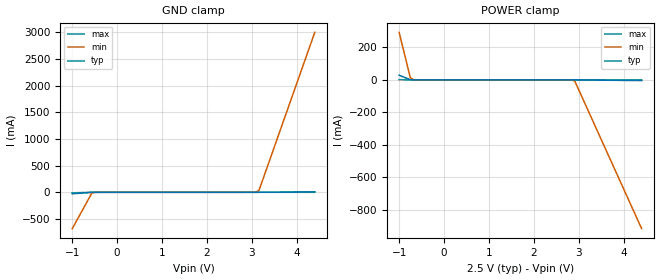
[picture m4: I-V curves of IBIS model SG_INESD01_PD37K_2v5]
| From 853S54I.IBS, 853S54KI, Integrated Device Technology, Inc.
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[Model] SG_INESD01_PD37K_2v5
Model_type   Input
Polarity   Non-Inverting
Vinl = 0.7V
Vinh = 1.7V
|   typ   min   max
C_comp   2pF   1.5pF   2.5pF
|   typ   min   max
[Voltage range]   2.5V   2.375V   2.625V
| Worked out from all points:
|   GND clamp passes 1 mA (typ) near -0.54 V on its own axis
|   POWER clamp passes 1 mA (typ) near -0.74 V on its own axis
[GND_clamp]
|Voltage   I (typ)   I (min)   I (max)
-999mV    -27.96mA   -681.8mA   -9.625mA
-564.6mV  -1.482mA   -16.24mA   -666.5uA
-502.5mV  -453.5uA   -2.74mA    -140.7uA
2.973V    79.17uA    336.2uA    73.41uA
3.097V    110.7uA    5.854mA    76.48uA
3.159V    212.3uA    36.85mA    78.12uA
4.4V      8.262mA    2.998A     129uA
[Power_clamp]
|Voltage   I (typ)   I (min)   I (max)
-999mV    28.57mA    291.8mA    1.724mA
-750.8mV  1.219mA    13.65mA    196.4uA
-688.7mV  336.8uA    2.373mA    103.4uA
2.724V    -5.968uA   -54uA      -2.456uA
2.911V    -51.42uA   -6.919mA   -7.069uA
4.4V      -4.421mA   -914.6mA   -50.62uA
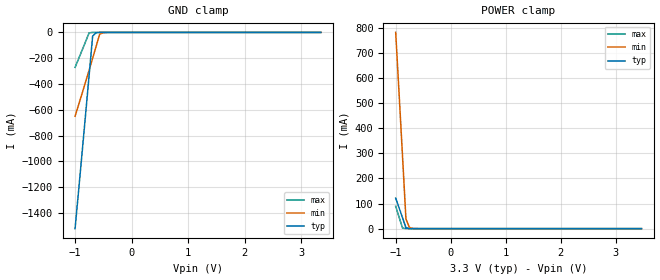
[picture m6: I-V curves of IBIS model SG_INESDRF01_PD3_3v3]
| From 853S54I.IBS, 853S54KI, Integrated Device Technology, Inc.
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[Model] SG_INESDRF01_PD3_3v3
Model_type   Input
Polarity   Non-Inverting
Vinl = 0.8V
Vinh = 2.0V
|   typ   min   max
C_comp   2pF   1.5pF   2.5pF
|   typ   min   max
[Voltage range]   3.3V   3.135V   3.465V
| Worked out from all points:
|   GND clamp passes 1 mA (typ) near -0.58 V on its own axis
|   POWER clamp passes 1 mA (typ) near -0.76 V on its own axis
[GND_clamp]
|Voltage   I (typ)   I (min)   I (max)
-999mV    -1.521A    -650.1mA   -270.9mA
-874.9mV  -933.7mA   -473mA     -138.4mA
-750.8mV  -334.2mA   -292.4mA   -3.26mA
-688.7mV  -29.87mA   -200.7mA   -164.7uA
-626.7mV  -2.683mA   -108mA     -22.2uA
-564.6mV  -253uA     -14.48mA   -14.25uA
-502.5mV  -34.49uA   -1.95mA    -12.42uA
3.345V    87.98uA    90.85uA    82.61uA
[Power_clamp]
|Voltage   I (typ)   I (min)   I (max)
-999mV    121.3mA    780.6mA    88.97mA
-874.9mV  43.47mA    288.5mA    2.188mA
-812.8mV  3.981mA    38.72mA    200.4uA
-750.8mV  452.5uA    5.275mA    108.4uA
-688.7mV  135.8uA    795.9uA    102.8uA
-564.6mV  101.9uA    112.9uA    99.51uA
3.469V    -4.449uA   -17.34uA   -102.2nA
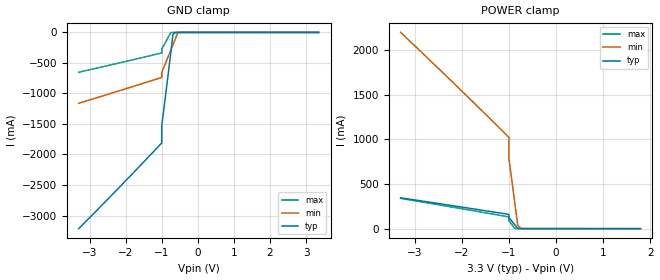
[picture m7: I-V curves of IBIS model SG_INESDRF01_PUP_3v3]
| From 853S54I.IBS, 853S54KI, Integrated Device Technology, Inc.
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[Model] SG_INESDRF01_PUP_3v3
Model_type   Input
Polarity   Non-Inverting
Vinl = 0.8V
Vinh = 2.0V
|   typ   min   max
C_comp   2pF   1.5pF   2.5pF
|   typ   min   max
[Voltage range]   3.3V   3.135V   3.465V
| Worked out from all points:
|   GND clamp passes 1 mA (typ) near -0.58 V on its own axis
|   POWER clamp passes 1 mA (typ) near -0.76 V on its own axis
[GND_clamp]
|Voltage   I (typ)   I (min)   I (max)
-3.3V     -3.215A    -1.161A    -652.8mA
-1V       -1.811A    -737.4mA   -336.3mA
-999mV    -1.521A    -650.2mA   -271mA
-750.8mV  -334.3mA   -292.5mA   -3.373mA
-688.7mV  -29.98mA   -200.8mA   -276.1uA
-626.7mV  -2.792mA   -108.1mA   -131.9uA
-564.6mV  -359.9uA   -14.58mA   -122.2uA
-502.5mV  -139.5uA   -2.051mA   -118.6uA
3.345V    93.13uA    98.93uA    85.56uA
[Power_clamp]
|Voltage   I (typ)   I (min)   I (max)
-3.3V     345.5mA    2.199A     339.1mA
-1.92V    235.1mA    1.5A       216mA
-1V       159.6mA    1.023A     131.7mA
-999mV    121.3mA    780.6mA    89mA
-874.9mV  43.5mA     288.5mA    2.22mA
-812.8mV  4.008mA    38.74mA    229.9uA
-750.8mV  477.9uA    5.298mA    136.1uA
1.794V    -7.889uA   -12.58uA   -3.241uA
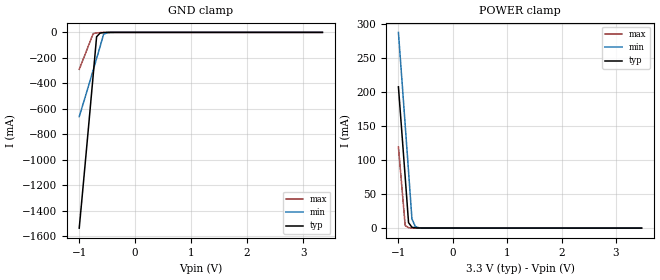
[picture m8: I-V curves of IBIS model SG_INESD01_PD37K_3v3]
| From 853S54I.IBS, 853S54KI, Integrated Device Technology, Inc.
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[Model] SG_INESD01_PD37K_3v3
Model_type   Input
Polarity   Non-Inverting
Vinl = 0.8V
Vinh = 2.0V
|   typ   min   max
C_comp   2pF   1.5pF   2.5pF
|   typ   min   max
[Voltage range]   3.3V   3.135V   3.465V
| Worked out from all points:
|   GND clamp passes 1 mA (typ) near -0.54 V on its own axis
|   POWER clamp passes 1 mA (typ) near -0.73 V on its own axis
[GND_clamp]
|Voltage   I (typ)   I (min)   I (max)
-999mV    -1.539A    -662.2mA   -290.3mA
-874.9mV  -945.9mA   -482.2mA   -151.5mA
-750.8mV  -341.2mA   -298.6mA   -9.863mA
-688.7mV  -34.3mA    -205.4mA   -4.112mA
-626.7mV  -5.265mA   -111.3mA   -1.946mA
-564.6mV  -1.482mA   -16.24mA   -666.5uA
-502.5mV  -453.5uA   -2.74mA    -140.7uA
-440.5mV  -107uA     -534.7uA   -26.11uA
3.345V    87.98uA    90.87uA    82.61uA
[Power_clamp]
|Voltage   I (typ)   I (min)   I (max)
-999mV    207.7mA    287.7mA    119.1mA
-874.9mV  75.29mA    152.1mA    3.77mA
-812.8mV  8.078mA    83.22mA    599.1uA
-750.8mV  1.24mA     13.67mA    217.1uA
-688.7mV  357.8uA    2.393mA    124.2uA
-626.7mV  164.2uA    593.7uA    104.2uA
-502.5mV  102.3uA    128.8uA    98.01uA
3.469V    -4.456uA   -38.03uA   -102.2nA
